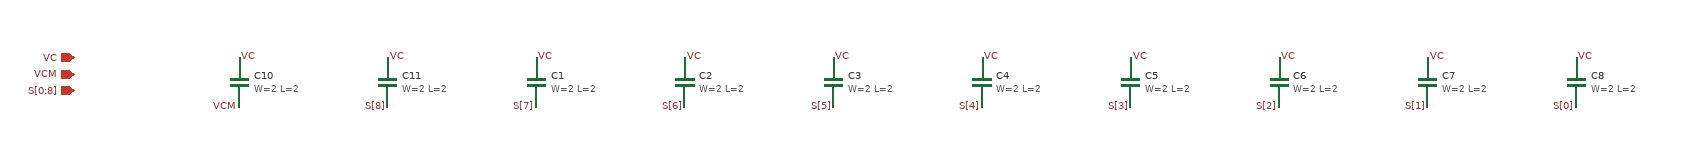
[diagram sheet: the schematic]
v {xschem version=3.4.8RC file_version=1.2}
G {}
K {}
V {}
S {}
F {}
E {}
C {sky130_fd_pr/cap_mim_m3_1.sym} 720 -90 0 0 {name=C1 model=cap_mim_m3_1 W=2 L=2 MF=2 spiceprefix=X}
C {sky130_fd_pr/cap_mim_m3_1.sym} 900 -90 0 0 {name=C2 model=cap_mim_m3_1 W=2 L=2 MF=4 spiceprefix=X}
C {sky130_fd_pr/cap_mim_m3_1.sym} 1080 -90 0 0 {name=C3 model=cap_mim_m3_1 W=2 L=2 MF=8 spiceprefix=X}
C {sky130_fd_pr/cap_mim_m3_1.sym} 1260 -90 0 0 {name=C4 model=cap_mim_m3_1 W=2 L=2 MF=16 spiceprefix=X}
C {sky130_fd_pr/cap_mim_m3_1.sym} 1440 -90 0 0 {name=C5 model=cap_mim_m3_1 W=2 L=2 MF=32 spiceprefix=X}
C {sky130_fd_pr/cap_mim_m3_1.sym} 1620 -90 0 0 {name=C6 model=cap_mim_m3_1 W=2 L=2 MF=64 spiceprefix=X}
C {sky130_fd_pr/cap_mim_m3_1.sym} 1800 -90 0 0 {name=C7 model=cap_mim_m3_1 W=2 L=2 MF=128 spiceprefix=X}
C {sky130_fd_pr/cap_mim_m3_1.sym} 1980 -90 0 0 {name=C8 model=cap_mim_m3_1 W=2 L=2 MF=256 spiceprefix=X}
C {lab_wire.sym} 720 -120 0 1 {name=p1 lab=VC}
C {lab_wire.sym} 540 -60 2 1 {name=p2 lab=S[8]}
C {lab_wire.sym} 900 -120 0 1 {name=p3 lab=VC}
C {lab_wire.sym} 720 -60 2 1 {name=p4 lab=S[7]}
C {lab_wire.sym} 1080 -120 0 1 {name=p5 lab=VC}
C {lab_wire.sym} 900 -60 2 1 {name=p6 lab=S[6]}
C {lab_wire.sym} 1260 -120 0 1 {name=p7 lab=VC}
C {lab_wire.sym} 1080 -60 2 1 {name=p8 lab=S[5]}
C {lab_wire.sym} 1440 -120 0 1 {name=p9 lab=VC}
C {lab_wire.sym} 1260 -60 2 1 {name=p10 lab=S[4]}
C {lab_wire.sym} 1620 -120 0 1 {name=p11 lab=VC}
C {lab_wire.sym} 1440 -60 2 1 {name=p12 lab=S[3]}
C {lab_wire.sym} 1800 -120 0 1 {name=p13 lab=VC}
C {lab_wire.sym} 1620 -60 2 1 {name=p14 lab=S[2]}
C {lab_wire.sym} 1980 -120 0 1 {name=p15 lab=VC}
C {lab_wire.sym} 1800 -60 2 1 {name=p16 lab=S[1]}
C {lab_wire.sym} 1980 -60 2 1 {name=p18 lab=S[0]}
C {iopin.sym} 160 -120 0 0 {name=p19 lab=VC}
C {iopin.sym} 160 -100 0 0 {name=p20 lab=VCM}
C {ipin.sym} 160 -80 0 0 {name=p21 lab=S[0:8]}
C {sky130_fd_pr/cap_mim_m3_1.sym} 360 -90 0 0 {name=C10 model=cap_mim_m3_1 W=2 L=2 MF=1 spiceprefix=X}
C {sky130_fd_pr/cap_mim_m3_1.sym} 540 -90 0 0 {name=C11 model=cap_mim_m3_1 W=2 L=2 MF=1 spiceprefix=X}
C {lab_wire.sym} 360 -120 0 1 {name=p22 lab=VC}
C {lab_wire.sym} 360 -60 2 1 {name=p23 lab=VCM}
C {lab_wire.sym} 540 -120 0 1 {name=p24 lab=VC}
